! (c) 2009  Infineon Technologies AG, Munich
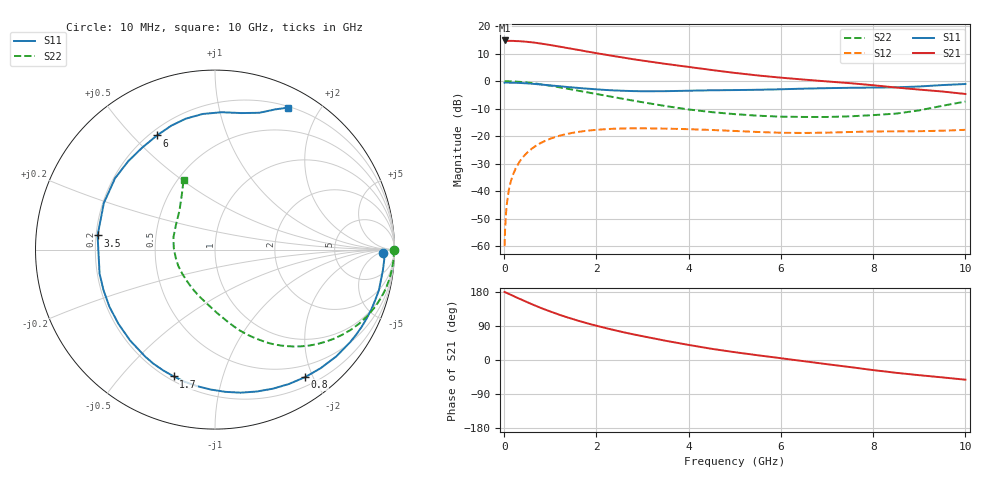
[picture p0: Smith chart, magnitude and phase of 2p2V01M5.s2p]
! Infineon Technologies  Discrete & RF Semiconductors
! BFP420
! VCE =  2.0 V,  IC =  1.5 mA
! Common Emitter S-Parameters:  Nov 2009
# GHz  S  MA  R  50
!  f  S11  S21  S12  S22
! GHz  MAG  ANG  MAG  ANG  MAG  ANG  MAG  ANG
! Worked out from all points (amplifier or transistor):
!   46 points, 10 MHz to 10 GHz, reference 50 ohm
!   highest |S21| = 14.8 dB at 10 MHz (marker M1)
!   |S21| within 3 dB of that: start of sweep to 1.456 GHz
!   unconditionally stable (mu >= 1): 4.136 GHz to end of sweep
!   at 300 MHz: K = 0.03, MSG = 22.4 dB, |S12| = -30.2 dB
!   at 1.7 GHz: K = 0.31, MSG = 14.7 dB, |S12| = -18.2 dB
!   at 10 GHz: K = 1.27, MAG = 3.4 dB, |S12| = -17.7 dB
!   lowest NFmin = 0.52 dB at 900 MHz
!   S11 on the Smith chart (normalised r, x): 10 MHz: 28, -10; 800 MHz: 0.32, -1.89; 1.7 GHz: 0.22, -0.70; 3.5 GHz: 0.21, +0.06; 6 GHz: 0.23, +0.59; 10 GHz: 0.21, +1.62
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0.01  0.9388 -1.3  5.51 179.4  0.001 85.9  0.9954 0.0
0.02  0.944 -1.5  5.352 179.2  0.002 86.1  0.996 -0.7
0.05  0.9444 -3.5  5.385 177.3  0.0052 89.5  0.9962 -2.0
0.1  0.9425 -7.0  5.42 174.6  0.0104 86.3  0.9948 -4.1
0.2  0.9408 -13.9  5.405 169.0  0.0207 82.0  0.9884 -8.1
0.35  0.9282 -24.3  5.33 160.7  0.036 75.8  0.9715 -14.1
0.5  0.9122 -34.6  5.197 152.6  0.0504 69.7  0.9459 -19.9
0.7  0.8852 -48.2  4.973 142.2  0.0679 61.8  0.9028 -27.2
0.8  0.8701 -54.7  4.83 137.3  0.0758 58.0  0.8786 -30.6
1  0.8391 -67.5  4.549 128.0  0.09 51.0  0.8267 -37.0
1.2  0.8097 -79.9  4.257 119.3  0.1019 44.5  0.774 -42.9
1.7  0.7432 -108.0  3.591 100.4  0.1228 30.5  0.6507 -55.3
2.2  0.693 -133.0  3.034 84.4  0.1342 19.1  0.5463 -65.2
2.6  0.6689 -151.6  2.674 72.9  0.1383 11.1  0.4744 -72.6
3  0.6571 -168.1  2.371 62.8  0.1391 4.6  0.4148 -79.2
3.5  0.659 173.1  2.066 50.8  0.1373 -2.3  0.353 -88.2
4.5  0.6842 144.5  1.6 29.5  0.1297 -12.1  0.274 -109.0
5.5  0.6983 125.4  1.272 12.5  0.1193 -17.0  0.2359 -130.9
6  0.7135 116.9  1.16 4.7  0.1155 -17.6  0.2267 -143.3
7  0.7476 102.5  0.991 -11.0  0.116 -17.7  0.2236 -168.6
8.5  0.7746 79.1  0.767 -33.8  0.1225 -22.1  0.2577 147.5
10  0.8892 62.8  0.586 -52.0  0.1306 -24.2  0.4269 114.2
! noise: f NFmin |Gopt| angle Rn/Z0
0.9  0.52  0.55  33  0.27
1.8  1.07  0.35  77  0.21
2.4  1.18  0.36  101  0.18
3  1.41  0.36  134  0.13
4  1.68  0.4  -172  0.1
5  2.08  0.44  -130  0.32
6  2.89  0.57  -114  0.39
